VERSION 5.7 ;
  NOWIREEXTENSIONATPIN ON ;
  DIVIDERCHAR "/" ;
  BUSBITCHARS "[]" ;
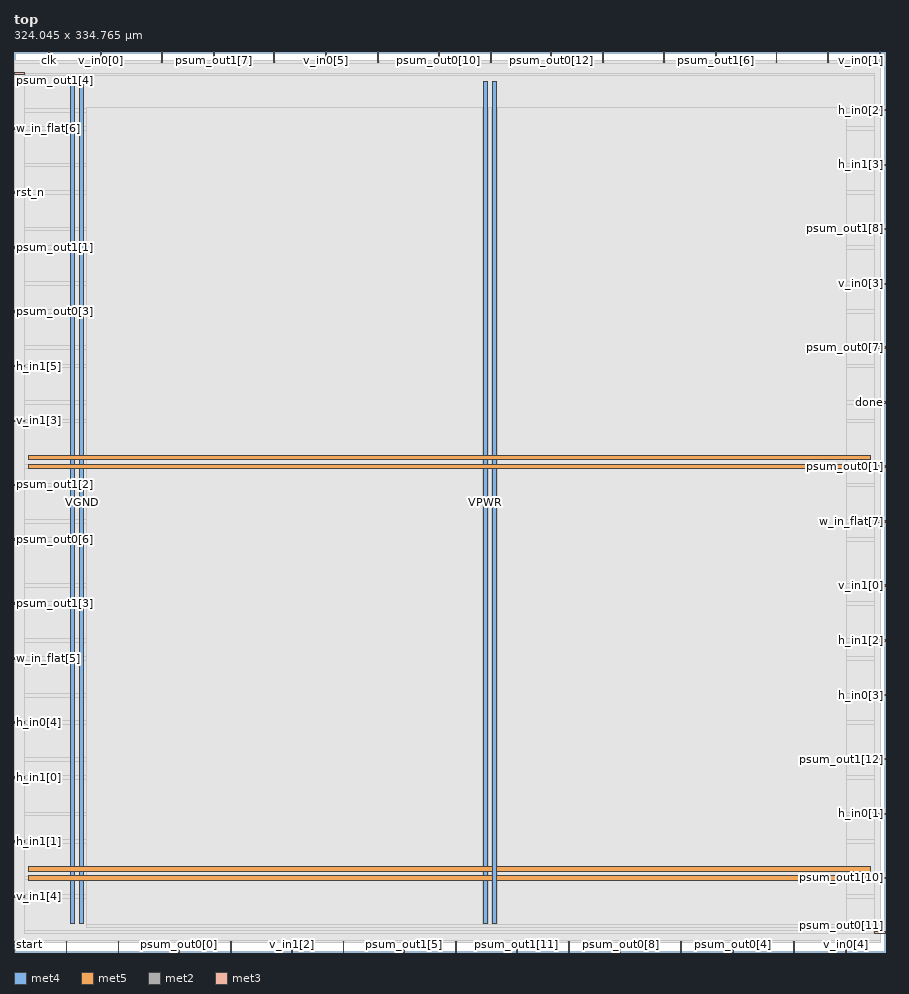
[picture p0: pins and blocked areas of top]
MACRO top
  CLASS BLOCK ;
  FOREIGN top ;
  ORIGIN 0.000 0.000 ;
  SIZE 324.045 BY 334.765 ;
  PIN VGND
    DIRECTION INOUT ;
    USE GROUND ;
    PORT
      LAYER met4 ;
        RECT 24.340 10.640 25.940 323.920 ;
    END
    PORT
      LAYER met4 ;
        RECT 177.940 10.640 179.540 323.920 ;
    END
    PORT
      LAYER met5 ;
        RECT 5.280 30.030 318.560 31.630 ;
    END
    PORT
      LAYER met5 ;
        RECT 5.280 183.210 318.560 184.810 ;
    END
  END VGND
  PIN VPWR
    DIRECTION INOUT ;
    USE POWER ;
    PORT
      LAYER met4 ;
        RECT 21.040 10.640 22.640 323.920 ;
    END
    PORT
      LAYER met4 ;
        RECT 174.640 10.640 176.240 323.920 ;
    END
    PORT
      LAYER met5 ;
        RECT 5.280 26.730 318.560 28.330 ;
    END
    PORT
      LAYER met5 ;
        RECT 5.280 179.910 318.560 181.510 ;
    END
  END VPWR
  PIN clk
    DIRECTION INPUT ;
    USE SIGNAL ;
    ANTENNAGATEAREA 1.286700 ;
    ANTENNADIFFAREA 0.434700 ;
    PORT
      LAYER met2 ;
        RECT 12.970 330.765 13.250 334.765 ;
    END
  END clk
  PIN done
    DIRECTION OUTPUT TRISTATE ;
    USE SIGNAL ;
    ANTENNADIFFAREA 0.445500 ;
    PORT
      LAYER met3 ;
        RECT 320.045 204.040 324.045 204.640 ;
    END
  END done
  PIN h_in0[0]
    DIRECTION INPUT ;
    USE SIGNAL ;
    ANTENNAGATEAREA 0.560700 ;
    ANTENNADIFFAREA 0.434700 ;
    PORT
      LAYER met2 ;
        RECT 241.590 330.765 241.870 334.765 ;
    END
  END h_in0[0]
  PIN h_in0[1]
    DIRECTION INPUT ;
    USE SIGNAL ;
    ANTENNAGATEAREA 0.631200 ;
    ANTENNADIFFAREA 0.434700 ;
    PORT
      LAYER met3 ;
        RECT 320.045 51.040 324.045 51.640 ;
    END
  END h_in0[1]
  PIN h_in0[2]
    DIRECTION INPUT ;
    USE SIGNAL ;
    ANTENNAGATEAREA 0.647700 ;
    ANTENNADIFFAREA 0.434700 ;
    PORT
      LAYER met3 ;
        RECT 320.045 312.840 324.045 313.440 ;
    END
  END h_in0[2]
  PIN h_in0[3]
    DIRECTION INPUT ;
    USE SIGNAL ;
    ANTENNAGATEAREA 0.631200 ;
    ANTENNADIFFAREA 0.434700 ;
    PORT
      LAYER met3 ;
        RECT 320.045 95.240 324.045 95.840 ;
    END
  END h_in0[3]
  PIN h_in0[4]
    DIRECTION INPUT ;
    USE SIGNAL ;
    ANTENNAGATEAREA 0.647700 ;
    ANTENNADIFFAREA 0.434700 ;
    PORT
      LAYER met3 ;
        RECT 0.000 85.040 4.000 85.640 ;
    END
  END h_in0[4]
  PIN h_in0[5]
    DIRECTION INPUT ;
    USE SIGNAL ;
    ANTENNAGATEAREA 0.647700 ;
    ANTENNADIFFAREA 0.434700 ;
    PORT
      LAYER met2 ;
        RECT 80.590 0.000 80.870 4.000 ;
    END
  END h_in0[5]
  PIN h_in1[0]
    DIRECTION INPUT ;
    USE SIGNAL ;
    ANTENNAGATEAREA 0.631200 ;
    ANTENNADIFFAREA 0.434700 ;
    PORT
      LAYER met3 ;
        RECT 0.000 64.640 4.000 65.240 ;
    END
  END h_in1[0]
  PIN h_in1[1]
    DIRECTION INPUT ;
    USE SIGNAL ;
    ANTENNAGATEAREA 0.631200 ;
    ANTENNADIFFAREA 0.434700 ;
    PORT
      LAYER met3 ;
        RECT 0.000 40.840 4.000 41.440 ;
    END
  END h_in1[1]
  PIN h_in1[2]
    DIRECTION INPUT ;
    USE SIGNAL ;
    ANTENNAGATEAREA 0.631200 ;
    ANTENNADIFFAREA 0.434700 ;
    PORT
      LAYER met3 ;
        RECT 320.045 115.640 324.045 116.240 ;
    END
  END h_in1[2]
  PIN h_in1[3]
    DIRECTION INPUT ;
    USE SIGNAL ;
    ANTENNAGATEAREA 0.647700 ;
    ANTENNADIFFAREA 0.434700 ;
    PORT
      LAYER met3 ;
        RECT 320.045 292.440 324.045 293.040 ;
    END
  END h_in1[3]
  PIN h_in1[4]
    DIRECTION INPUT ;
    USE SIGNAL ;
    ANTENNAGATEAREA 0.631200 ;
    ANTENNADIFFAREA 0.434700 ;
    PORT
      LAYER met2 ;
        RECT 19.410 0.000 19.690 4.000 ;
    END
  END h_in1[4]
  PIN h_in1[5]
    DIRECTION INPUT ;
    USE SIGNAL ;
    ANTENNAGATEAREA 0.560700 ;
    ANTENNADIFFAREA 0.434700 ;
    PORT
      LAYER met3 ;
        RECT 0.000 217.640 4.000 218.240 ;
    END
  END h_in1[5]
  PIN psum_out0[0]
    DIRECTION OUTPUT TRISTATE ;
    USE SIGNAL ;
    ANTENNADIFFAREA 0.795200 ;
    PORT
      LAYER met2 ;
        RECT 61.270 0.000 61.550 4.000 ;
    END
  END psum_out0[0]
  PIN psum_out0[10]
    DIRECTION OUTPUT TRISTATE ;
    USE SIGNAL ;
    ANTENNADIFFAREA 0.795200 ;
    PORT
      LAYER met2 ;
        RECT 157.870 330.765 158.150 334.765 ;
    END
  END psum_out0[10]
  PIN psum_out0[11]
    DIRECTION OUTPUT TRISTATE ;
    USE SIGNAL ;
    ANTENNADIFFAREA 0.795200 ;
    PORT
      LAYER met3 ;
        RECT 320.045 6.840 324.045 7.440 ;
    END
  END psum_out0[11]
  PIN psum_out0[12]
    DIRECTION OUTPUT TRISTATE ;
    USE SIGNAL ;
    ANTENNADIFFAREA 0.795200 ;
    PORT
      LAYER met2 ;
        RECT 199.730 330.765 200.010 334.765 ;
    END
  END psum_out0[12]
  PIN psum_out0[1]
    DIRECTION OUTPUT TRISTATE ;
    USE SIGNAL ;
    ANTENNADIFFAREA 0.795200 ;
    PORT
      LAYER met3 ;
        RECT 320.045 180.240 324.045 180.840 ;
    END
  END psum_out0[1]
  PIN psum_out0[2]
    DIRECTION OUTPUT TRISTATE ;
    USE SIGNAL ;
    ANTENNADIFFAREA 0.795200 ;
    PORT
      LAYER met2 ;
        RECT 135.330 330.765 135.610 334.765 ;
    END
  END psum_out0[2]
  PIN psum_out0[3]
    DIRECTION OUTPUT TRISTATE ;
    USE SIGNAL ;
    ANTENNADIFFAREA 0.795200 ;
    PORT
      LAYER met3 ;
        RECT 0.000 238.040 4.000 238.640 ;
    END
  END psum_out0[3]
  PIN psum_out0[4]
    DIRECTION OUTPUT TRISTATE ;
    USE SIGNAL ;
    ANTENNADIFFAREA 0.795200 ;
    PORT
      LAYER met2 ;
        RECT 267.350 0.000 267.630 4.000 ;
    END
  END psum_out0[4]
  PIN psum_out0[5]
    DIRECTION OUTPUT TRISTATE ;
    USE SIGNAL ;
    ANTENNADIFFAREA 0.795200 ;
    PORT
      LAYER met2 ;
        RECT 248.030 0.000 248.310 4.000 ;
    END
  END psum_out0[5]
  PIN psum_out0[6]
    DIRECTION OUTPUT TRISTATE ;
    USE SIGNAL ;
    ANTENNADIFFAREA 0.795200 ;
    PORT
      LAYER met3 ;
        RECT 0.000 153.040 4.000 153.640 ;
    END
  END psum_out0[6]
  PIN psum_out0[7]
    DIRECTION OUTPUT TRISTATE ;
    USE SIGNAL ;
    ANTENNADIFFAREA 0.795200 ;
    PORT
      LAYER met3 ;
        RECT 320.045 224.440 324.045 225.040 ;
    END
  END psum_out0[7]
  PIN psum_out0[8]
    DIRECTION OUTPUT TRISTATE ;
    USE SIGNAL ;
    ANTENNADIFFAREA 0.795200 ;
    PORT
      LAYER met2 ;
        RECT 225.490 0.000 225.770 4.000 ;
    END
  END psum_out0[8]
  PIN psum_out0[9]
    DIRECTION OUTPUT TRISTATE ;
    USE SIGNAL ;
    ANTENNADIFFAREA 0.795200 ;
    PORT
      LAYER met2 ;
        RECT 219.050 330.765 219.330 334.765 ;
    END
  END psum_out0[9]
  PIN psum_out1[0]
    DIRECTION OUTPUT TRISTATE ;
    USE SIGNAL ;
    ANTENNADIFFAREA 0.795200 ;
    PORT
      LAYER met2 ;
        RECT 289.890 0.000 290.170 4.000 ;
    END
  END psum_out1[0]
  PIN psum_out1[10]
    DIRECTION OUTPUT TRISTATE ;
    USE SIGNAL ;
    ANTENNADIFFAREA 0.795200 ;
    PORT
      LAYER met3 ;
        RECT 320.045 27.240 324.045 27.840 ;
    END
  END psum_out1[10]
  PIN psum_out1[11]
    DIRECTION OUTPUT TRISTATE ;
    USE SIGNAL ;
    ANTENNADIFFAREA 0.795200 ;
    PORT
      LAYER met2 ;
        RECT 186.850 0.000 187.130 4.000 ;
    END
  END psum_out1[11]
  PIN psum_out1[12]
    DIRECTION OUTPUT TRISTATE ;
    USE SIGNAL ;
    ANTENNADIFFAREA 0.445500 ;
    PORT
      LAYER met3 ;
        RECT 320.045 71.440 324.045 72.040 ;
    END
  END psum_out1[12]
  PIN psum_out1[1]
    DIRECTION OUTPUT TRISTATE ;
    USE SIGNAL ;
    ANTENNADIFFAREA 0.795200 ;
    PORT
      LAYER met3 ;
        RECT 0.000 261.840 4.000 262.440 ;
    END
  END psum_out1[1]
  PIN psum_out1[2]
    DIRECTION OUTPUT TRISTATE ;
    USE SIGNAL ;
    ANTENNADIFFAREA 0.795200 ;
    PORT
      LAYER met3 ;
        RECT 0.000 173.440 4.000 174.040 ;
    END
  END psum_out1[2]
  PIN psum_out1[3]
    DIRECTION OUTPUT TRISTATE ;
    USE SIGNAL ;
    ANTENNADIFFAREA 0.795200 ;
    PORT
      LAYER met3 ;
        RECT 0.000 129.240 4.000 129.840 ;
    END
  END psum_out1[3]
  PIN psum_out1[4]
    DIRECTION OUTPUT TRISTATE ;
    USE SIGNAL ;
    ANTENNADIFFAREA 0.795200 ;
    PORT
      LAYER met3 ;
        RECT 0.000 326.440 4.000 327.040 ;
    END
  END psum_out1[4]
  PIN psum_out1[5]
    DIRECTION OUTPUT TRISTATE ;
    USE SIGNAL ;
    ANTENNADIFFAREA 0.795200 ;
    PORT
      LAYER met2 ;
        RECT 144.990 0.000 145.270 4.000 ;
    END
  END psum_out1[5]
  PIN psum_out1[6]
    DIRECTION OUTPUT TRISTATE ;
    USE SIGNAL ;
    ANTENNADIFFAREA 0.795200 ;
    PORT
      LAYER met2 ;
        RECT 260.910 330.765 261.190 334.765 ;
    END
  END psum_out1[6]
  PIN psum_out1[7]
    DIRECTION OUTPUT TRISTATE ;
    USE SIGNAL ;
    ANTENNADIFFAREA 0.795200 ;
    PORT
      LAYER met2 ;
        RECT 74.150 330.765 74.430 334.765 ;
    END
  END psum_out1[7]
  PIN psum_out1[8]
    DIRECTION OUTPUT TRISTATE ;
    USE SIGNAL ;
    ANTENNADIFFAREA 0.795200 ;
    PORT
      LAYER met3 ;
        RECT 320.045 268.640 324.045 269.240 ;
    END
  END psum_out1[8]
  PIN psum_out1[9]
    DIRECTION OUTPUT TRISTATE ;
    USE SIGNAL ;
    ANTENNADIFFAREA 0.795200 ;
    PORT
      LAYER met2 ;
        RECT 177.190 330.765 177.470 334.765 ;
    END
  END psum_out1[9]
  PIN rst_n
    DIRECTION INPUT ;
    USE SIGNAL ;
    ANTENNAGATEAREA 1.286700 ;
    ANTENNADIFFAREA 0.434700 ;
    PORT
      LAYER met3 ;
        RECT 0.000 282.240 4.000 282.840 ;
    END
  END rst_n
  PIN start
    DIRECTION INPUT ;
    USE SIGNAL ;
    ANTENNAGATEAREA 0.593700 ;
    ANTENNADIFFAREA 0.434700 ;
    PORT
      LAYER met2 ;
        RECT 0.090 0.000 0.370 4.000 ;
    END
  END start
  PIN v_in0[0]
    DIRECTION INPUT ;
    USE SIGNAL ;
    ANTENNAGATEAREA 0.631200 ;
    ANTENNADIFFAREA 0.434700 ;
    PORT
      LAYER met2 ;
        RECT 32.290 330.765 32.570 334.765 ;
    END
  END v_in0[0]
  PIN v_in0[1]
    DIRECTION INPUT ;
    USE SIGNAL ;
    ANTENNAGATEAREA 0.647700 ;
    ANTENNADIFFAREA 0.434700 ;
    PORT
      LAYER met2 ;
        RECT 322.090 330.765 322.370 334.765 ;
    END
  END v_in0[1]
  PIN v_in0[2]
    DIRECTION INPUT ;
    USE SIGNAL ;
    ANTENNAGATEAREA 0.647700 ;
    ANTENNADIFFAREA 0.434700 ;
    PORT
      LAYER met2 ;
        RECT 122.450 0.000 122.730 4.000 ;
    END
  END v_in0[2]
  PIN v_in0[3]
    DIRECTION INPUT ;
    USE SIGNAL ;
    ANTENNAGATEAREA 0.647700 ;
    ANTENNADIFFAREA 0.434700 ;
    PORT
      LAYER met3 ;
        RECT 320.045 248.240 324.045 248.840 ;
    END
  END v_in0[3]
  PIN v_in0[4]
    DIRECTION INPUT ;
    USE SIGNAL ;
    ANTENNAGATEAREA 0.647700 ;
    ANTENNADIFFAREA 0.434700 ;
    PORT
      LAYER met2 ;
        RECT 309.210 0.000 309.490 4.000 ;
    END
  END v_in0[4]
  PIN v_in0[5]
    DIRECTION INPUT ;
    USE SIGNAL ;
    ANTENNAGATEAREA 0.631200 ;
    ANTENNADIFFAREA 0.434700 ;
    PORT
      LAYER met2 ;
        RECT 116.010 330.765 116.290 334.765 ;
    END
  END v_in0[5]
  PIN v_in1[0]
    DIRECTION INPUT ;
    USE SIGNAL ;
    ANTENNAGATEAREA 0.647700 ;
    ANTENNADIFFAREA 0.434700 ;
    PORT
      LAYER met3 ;
        RECT 320.045 136.040 324.045 136.640 ;
    END
  END v_in1[0]
  PIN v_in1[1]
    DIRECTION INPUT ;
    USE SIGNAL ;
    ANTENNAGATEAREA 0.631200 ;
    ANTENNADIFFAREA 0.434700 ;
    PORT
      LAYER met2 ;
        RECT 38.730 0.000 39.010 4.000 ;
    END
  END v_in1[1]
  PIN v_in1[2]
    DIRECTION INPUT ;
    USE SIGNAL ;
    ANTENNAGATEAREA 0.631200 ;
    ANTENNADIFFAREA 0.434700 ;
    PORT
      LAYER met2 ;
        RECT 103.130 0.000 103.410 4.000 ;
    END
  END v_in1[2]
  PIN v_in1[3]
    DIRECTION INPUT ;
    USE SIGNAL ;
    ANTENNAGATEAREA 0.631200 ;
    ANTENNADIFFAREA 0.434700 ;
    PORT
      LAYER met3 ;
        RECT 0.000 197.240 4.000 197.840 ;
    END
  END v_in1[3]
  PIN v_in1[4]
    DIRECTION INPUT ;
    USE SIGNAL ;
    ANTENNAGATEAREA 0.631200 ;
    ANTENNADIFFAREA 0.434700 ;
    PORT
      LAYER met3 ;
        RECT 0.000 20.440 4.000 21.040 ;
    END
  END v_in1[4]
  PIN v_in1[5]
    DIRECTION INPUT ;
    USE SIGNAL ;
    ANTENNAGATEAREA 0.631200 ;
    ANTENNADIFFAREA 0.434700 ;
    PORT
      LAYER met2 ;
        RECT 164.310 0.000 164.590 4.000 ;
    END
  END v_in1[5]
  PIN w_in_flat[0]
    DIRECTION INPUT ;
    USE SIGNAL ;
    ANTENNAGATEAREA 0.631200 ;
    ANTENNADIFFAREA 0.434700 ;
    PORT
      LAYER met2 ;
        RECT 302.770 330.765 303.050 334.765 ;
    END
  END w_in_flat[0]
  PIN w_in_flat[1]
    DIRECTION INPUT ;
    USE SIGNAL ;
    ANTENNAGATEAREA 0.631200 ;
    ANTENNADIFFAREA 0.434700 ;
    PORT
      LAYER met2 ;
        RECT 283.450 330.765 283.730 334.765 ;
    END
  END w_in_flat[1]
  PIN w_in_flat[2]
    DIRECTION INPUT ;
    USE SIGNAL ;
    ANTENNAGATEAREA 0.631200 ;
    ANTENNADIFFAREA 0.434700 ;
    PORT
      LAYER met2 ;
        RECT 54.830 330.765 55.110 334.765 ;
    END
  END w_in_flat[2]
  PIN w_in_flat[3]
    DIRECTION INPUT ;
    USE SIGNAL ;
    ANTENNAGATEAREA 0.631200 ;
    ANTENNADIFFAREA 0.434700 ;
    PORT
      LAYER met2 ;
        RECT 96.690 330.765 96.970 334.765 ;
    END
  END w_in_flat[3]
  PIN w_in_flat[4]
    DIRECTION INPUT ;
    USE SIGNAL ;
    ANTENNAGATEAREA 0.631200 ;
    ANTENNADIFFAREA 0.434700 ;
    PORT
      LAYER met2 ;
        RECT 206.170 0.000 206.450 4.000 ;
    END
  END w_in_flat[4]
  PIN w_in_flat[5]
    DIRECTION INPUT ;
    USE SIGNAL ;
    ANTENNAGATEAREA 0.647700 ;
    ANTENNADIFFAREA 0.434700 ;
    PORT
      LAYER met3 ;
        RECT 0.000 108.840 4.000 109.440 ;
    END
  END w_in_flat[5]
  PIN w_in_flat[6]
    DIRECTION INPUT ;
    USE SIGNAL ;
    ANTENNAGATEAREA 0.560700 ;
    ANTENNADIFFAREA 0.434700 ;
    PORT
      LAYER met3 ;
        RECT 0.000 306.040 4.000 306.640 ;
    END
  END w_in_flat[6]
  PIN w_in_flat[7]
    DIRECTION INPUT ;
    USE SIGNAL ;
    ANTENNAGATEAREA 0.631200 ;
    ANTENNADIFFAREA 0.434700 ;
    PORT
      LAYER met3 ;
        RECT 320.045 159.840 324.045 160.440 ;
    END
  END w_in_flat[7]
  OBS
      LAYER li1 ;
        RECT 5.520 10.795 318.320 323.765 ;
      LAYER met1 ;
        RECT 0.070 10.640 322.390 323.920 ;
      LAYER met2 ;
        RECT 0.100 330.485 12.690 331.570 ;
        RECT 13.530 330.485 32.010 331.570 ;
        RECT 32.850 330.485 54.550 331.570 ;
        RECT 55.390 330.485 73.870 331.570 ;
        RECT 74.710 330.485 96.410 331.570 ;
        RECT 97.250 330.485 115.730 331.570 ;
        RECT 116.570 330.485 135.050 331.570 ;
        RECT 135.890 330.485 157.590 331.570 ;
        RECT 158.430 330.485 176.910 331.570 ;
        RECT 177.750 330.485 199.450 331.570 ;
        RECT 200.290 330.485 218.770 331.570 ;
        RECT 219.610 330.485 241.310 331.570 ;
        RECT 242.150 330.485 260.630 331.570 ;
        RECT 261.470 330.485 283.170 331.570 ;
        RECT 284.010 330.485 302.490 331.570 ;
        RECT 303.330 330.485 321.810 331.570 ;
        RECT 0.100 4.280 322.360 330.485 ;
        RECT 0.650 3.670 19.130 4.280 ;
        RECT 19.970 3.670 38.450 4.280 ;
        RECT 39.290 3.670 60.990 4.280 ;
        RECT 61.830 3.670 80.310 4.280 ;
        RECT 81.150 3.670 102.850 4.280 ;
        RECT 103.690 3.670 122.170 4.280 ;
        RECT 123.010 3.670 144.710 4.280 ;
        RECT 145.550 3.670 164.030 4.280 ;
        RECT 164.870 3.670 186.570 4.280 ;
        RECT 187.410 3.670 205.890 4.280 ;
        RECT 206.730 3.670 225.210 4.280 ;
        RECT 226.050 3.670 247.750 4.280 ;
        RECT 248.590 3.670 267.070 4.280 ;
        RECT 267.910 3.670 289.610 4.280 ;
        RECT 290.450 3.670 308.930 4.280 ;
        RECT 309.770 3.670 322.360 4.280 ;
      LAYER met3 ;
        RECT 4.400 326.040 320.045 326.890 ;
        RECT 3.990 313.840 320.045 326.040 ;
        RECT 3.990 312.440 319.645 313.840 ;
        RECT 3.990 307.040 320.045 312.440 ;
        RECT 4.400 305.640 320.045 307.040 ;
        RECT 3.990 293.440 320.045 305.640 ;
        RECT 3.990 292.040 319.645 293.440 ;
        RECT 3.990 283.240 320.045 292.040 ;
        RECT 4.400 281.840 320.045 283.240 ;
        RECT 3.990 269.640 320.045 281.840 ;
        RECT 3.990 268.240 319.645 269.640 ;
        RECT 3.990 262.840 320.045 268.240 ;
        RECT 4.400 261.440 320.045 262.840 ;
        RECT 3.990 249.240 320.045 261.440 ;
        RECT 3.990 247.840 319.645 249.240 ;
        RECT 3.990 239.040 320.045 247.840 ;
        RECT 4.400 237.640 320.045 239.040 ;
        RECT 3.990 225.440 320.045 237.640 ;
        RECT 3.990 224.040 319.645 225.440 ;
        RECT 3.990 218.640 320.045 224.040 ;
        RECT 4.400 217.240 320.045 218.640 ;
        RECT 3.990 205.040 320.045 217.240 ;
        RECT 3.990 203.640 319.645 205.040 ;
        RECT 3.990 198.240 320.045 203.640 ;
        RECT 4.400 196.840 320.045 198.240 ;
        RECT 3.990 181.240 320.045 196.840 ;
        RECT 3.990 179.840 319.645 181.240 ;
        RECT 3.990 174.440 320.045 179.840 ;
        RECT 4.400 173.040 320.045 174.440 ;
        RECT 3.990 160.840 320.045 173.040 ;
        RECT 3.990 159.440 319.645 160.840 ;
        RECT 3.990 154.040 320.045 159.440 ;
        RECT 4.400 152.640 320.045 154.040 ;
        RECT 3.990 137.040 320.045 152.640 ;
        RECT 3.990 135.640 319.645 137.040 ;
        RECT 3.990 130.240 320.045 135.640 ;
        RECT 4.400 128.840 320.045 130.240 ;
        RECT 3.990 116.640 320.045 128.840 ;
        RECT 3.990 115.240 319.645 116.640 ;
        RECT 3.990 109.840 320.045 115.240 ;
        RECT 4.400 108.440 320.045 109.840 ;
        RECT 3.990 96.240 320.045 108.440 ;
        RECT 3.990 94.840 319.645 96.240 ;
        RECT 3.990 86.040 320.045 94.840 ;
        RECT 4.400 84.640 320.045 86.040 ;
        RECT 3.990 72.440 320.045 84.640 ;
        RECT 3.990 71.040 319.645 72.440 ;
        RECT 3.990 65.640 320.045 71.040 ;
        RECT 4.400 64.240 320.045 65.640 ;
        RECT 3.990 52.040 320.045 64.240 ;
        RECT 3.990 50.640 319.645 52.040 ;
        RECT 3.990 41.840 320.045 50.640 ;
        RECT 4.400 40.440 320.045 41.840 ;
        RECT 3.990 28.240 320.045 40.440 ;
        RECT 3.990 26.840 319.645 28.240 ;
        RECT 3.990 21.440 320.045 26.840 ;
        RECT 4.400 20.040 320.045 21.440 ;
        RECT 3.990 7.840 320.045 20.040 ;
        RECT 3.990 6.975 319.645 7.840 ;
      LAYER met4 ;
        RECT 26.975 10.240 174.240 313.985 ;
        RECT 176.640 10.240 177.540 313.985 ;
        RECT 179.940 10.240 309.745 313.985 ;
        RECT 26.975 9.015 309.745 10.240 ;
  END
END top
END LIBRARY

